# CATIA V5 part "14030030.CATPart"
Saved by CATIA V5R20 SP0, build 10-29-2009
Part number: 14030030
Definition: NONE
Nomenclature: 14030030
Source: Unknown
Description: 14030030
Bounding box of the stored display mesh (mm): x -15 to 60, y -29 to 18.906, z -19.1 to 19.1
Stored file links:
  C:\Users\Utente\Desktop\IO LAVORO\3D X SITO CF\X SITO\PLASTICA\RF2\14030030.CATPart

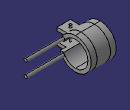
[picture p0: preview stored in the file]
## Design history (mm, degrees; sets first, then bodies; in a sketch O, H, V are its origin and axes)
Body1 "14030030" (main body)
  Solid1: solid without history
